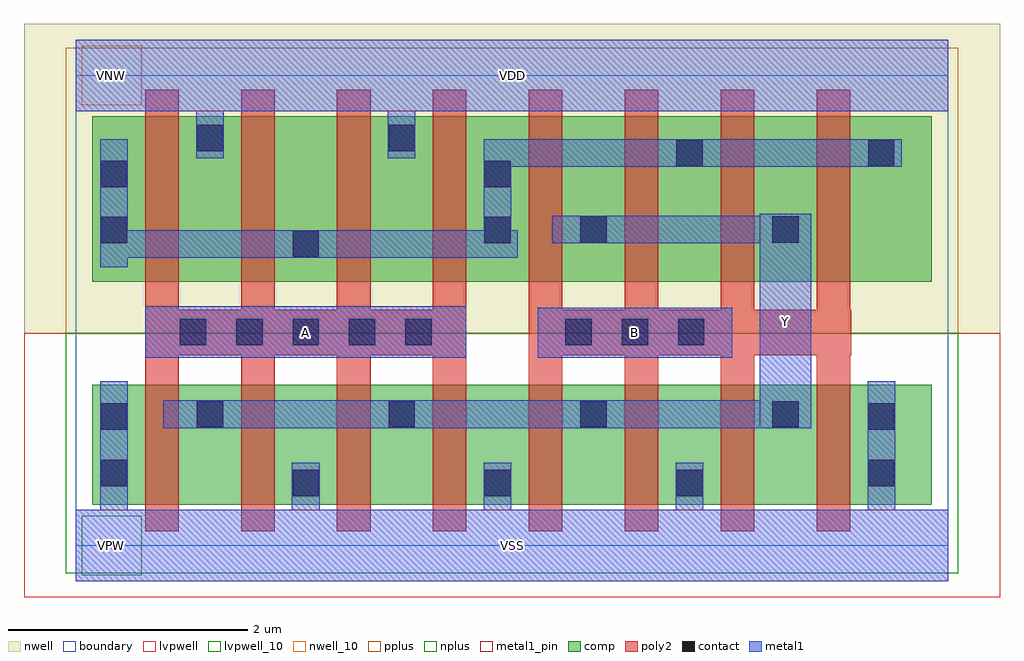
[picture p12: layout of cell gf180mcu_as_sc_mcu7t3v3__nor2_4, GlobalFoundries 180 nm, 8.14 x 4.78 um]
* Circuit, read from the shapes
.subckt gf180mcu_as_sc_mcu7t3v3__nor2_4 A B VDD VNW VSS Y
XM1 Y A VSS VSUBS nfet_03v3 w=1u l=0.28u m=4
XM2 Y B VSS VSUBS nfet_03v3 w=1u l=0.28u m=4
XM3 VDD A n1 VNW pfet_03v3 w=1.38u l=0.28u m=4
XM4 Y B n1 VNW pfet_03v3 w=1.38u l=0.28u m=4
.ends

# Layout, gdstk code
import gdstk
lib = gdstk.Library(unit=1e-6, precision=1e-09)
def R(c, l, rs):  # rectangles x0, y0, x1, y1
    for r in rs: c.add(gdstk.rectangle(r[:2], r[2:], *l))
def A(c, l, x, y, w, h, nx, ny, dx, dy):  # array of equal rectangles
    R(c, l, [(x+i*dx, y+j*dy, x+i*dx+w, y+j*dy+h) for i in range(nx) for j in range(ny)])
boundary = (0, 0)
nwell = (21, 0)
nwell_10 = (21, 10)
comp = (22, 0)
poly2 = (30, 0)
pplus = (31, 0)
nplus = (32, 0)
contact = (33, 0)
metal1 = (34, 0)
metal1_pin = (34, 10)
lvpwell = (204, 0)
lvpwell_10 = (204, 10)

gf180mcu_as_sc_mcu7t3v3_ = lib.new_cell('gf180mcu_as_sc_mcu7t3v3__nor2_4')
R(gf180mcu_as_sc_mcu7t3v3_, boundary, [(0,0,7.28,3.92)])
R(gf180mcu_as_sc_mcu7t3v3_, nwell, [(-0.43,1.77,7.71,4.35)])
R(gf180mcu_as_sc_mcu7t3v3_, nwell_10, [(0.05,3.67,0.55,4.17)])
R(gf180mcu_as_sc_mcu7t3v3_, comp, [(0.14,0.34,7.14,1.34), (0.14,2.2,7.14,3.58)])
A(gf180mcu_as_sc_mcu7t3v3_, poly2, 0.58, 0.12, 0.28, 1.465, 8, 1, 0.8, 0)
A(gf180mcu_as_sc_mcu7t3v3_, poly2, 0.58, 1.965, 0.28, 1.835, 8, 1, 0.8, 0)
R(gf180mcu_as_sc_mcu7t3v3_, poly2, [(0.58,1.585,3.26,1.965), (3.78,1.585,6.47,1.965)])
R(gf180mcu_as_sc_mcu7t3v3_, pplus, [(-0.08,1.77,7.36,4.15)])
R(gf180mcu_as_sc_mcu7t3v3_, nplus, [(-0.08,-0.23,7.36,1.77)])
A(gf180mcu_as_sc_mcu7t3v3_, contact, 1.81, 0.41, 0.22, 0.22, 3, 1, 1.6, 0)
A(gf180mcu_as_sc_mcu7t3v3_, contact, 1.01, 0.985, 0.22, 0.22, 4, 1, 1.6, 0)
A(gf180mcu_as_sc_mcu7t3v3_, contact, 0.87, 1.67, 0.22, 0.22, 5, 1, 0.47, 0)
A(gf180mcu_as_sc_mcu7t3v3_, contact, 4.085, 1.67, 0.22, 0.22, 3, 1, 0.47, 0)
R(gf180mcu_as_sc_mcu7t3v3_, contact, [(0.21,0.495,0.43,0.715), (6.61,0.495,6.83,0.715), (0.21,0.965,0.43,1.185), (6.61,0.965,6.83,1.185), (1.81,2.405,2.03,2.625), (0.21,2.52,0.43,2.74), (3.41,2.52,3.63,2.74), (4.21,2.525,4.43,2.745), (5.81,2.525,6.03,2.745), (0.21,2.99,0.43,3.21), (3.41,2.99,3.63,3.21), (5.01,3.165,5.23,3.385), (6.61,3.165,6.83,3.385), (1.01,3.29,1.23,3.51), (2.61,3.29,2.83,3.51)])
A(gf180mcu_as_sc_mcu7t3v3_, metal1, 1.805, 0.3, 0.23, 0.39, 3, 1, 1.6, 0)
R(gf180mcu_as_sc_mcu7t3v3_, metal1, [(0,-0.3,7.28,0.3), (0.205,0.3,0.435,1.37), (6.605,0.3,6.835,1.37), (0.73,0.98,6.135,1.21), (5.705,1.21,6.135,2.52), (0.58,1.565,3.26,1.995), (3.855,1.565,5.475,1.985), (0.205,2.32,0.435,2.4), (0.205,2.4,3.69,2.63), (3.975,2.52,6.135,2.75), (0.205,2.63,0.435,3.39), (3.405,2.63,3.635,3.16), (5.705,2.75,6.135,2.765), (3.405,3.16,6.89,3.39), (1.005,3.23,1.235,3.62), (2.605,3.23,2.835,3.62), (0,3.62,7.28,4.22)])
R(gf180mcu_as_sc_mcu7t3v3_, metal1_pin, [(0,-0.3,7.28,0.3), (5.705,0.98,6.135,2.765), (0.58,1.565,3.26,1.995), (3.855,1.565,5.475,1.985), (0,3.62,7.28,4.22)])
R(gf180mcu_as_sc_mcu7t3v3_, lvpwell, [(-0.43,-0.43,7.71,1.77)])
R(gf180mcu_as_sc_mcu7t3v3_, lvpwell_10, [(0.05,-0.25,0.55,0.25)])
gf180mcu_as_sc_mcu7t3v3_.add(gdstk.Label('VDD', (3.64,3.92), layer=34, texttype=10))
gf180mcu_as_sc_mcu7t3v3_.add(gdstk.Label('VSS', (3.64,0), layer=34, texttype=10))
gf180mcu_as_sc_mcu7t3v3_.add(gdstk.Label('Y', (5.92,1.872), layer=34, texttype=10))
gf180mcu_as_sc_mcu7t3v3_.add(gdstk.Label('A', (1.92,1.78), layer=34, texttype=10))
gf180mcu_as_sc_mcu7t3v3_.add(gdstk.Label('B', (4.665,1.775), layer=34, texttype=10))
gf180mcu_as_sc_mcu7t3v3_.add(gdstk.Label('VNW', (0.3,3.92), layer=21, texttype=10))
gf180mcu_as_sc_mcu7t3v3_.add(gdstk.Label('VPW', (0.3,0), layer=204, texttype=10))

lib.write_gds('gf180mcu_as_sc_mcu7t3v3__nor2_4.gds')
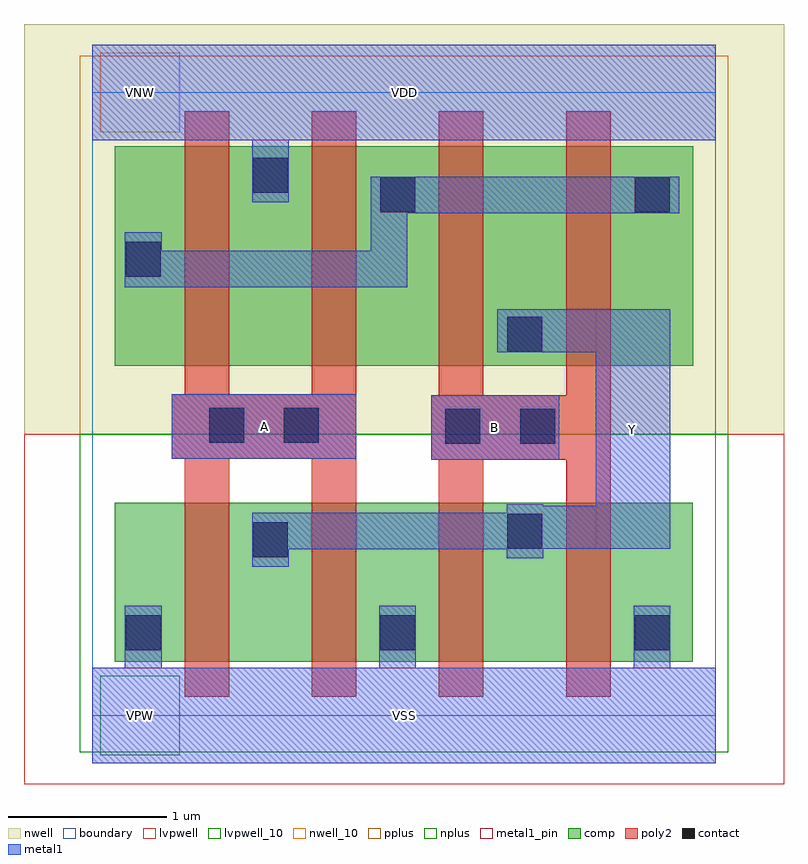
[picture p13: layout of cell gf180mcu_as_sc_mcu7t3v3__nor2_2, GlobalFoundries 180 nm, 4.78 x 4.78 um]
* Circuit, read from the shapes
.subckt gf180mcu_as_sc_mcu7t3v3__nor2_2 A B VDD VNW VSS Y
XM1 Y A VSS VSUBS nfet_03v3 w=1u l=0.28u m=2
XM2 Y B VSS VSUBS nfet_03v3 w=1u l=0.28u m=2
XM3 VDD A n1 VNW pfet_03v3 w=1.38u l=0.28u m=2
XM4 Y B n1 VNW pfet_03v3 w=1.38u l=0.28u m=2
.ends

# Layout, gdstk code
import gdstk
lib = gdstk.Library(unit=1e-6, precision=1e-09)
def R(c, l, rs):  # rectangles x0, y0, x1, y1
    for r in rs: c.add(gdstk.rectangle(r[:2], r[2:], *l))
def A(c, l, x, y, w, h, nx, ny, dx, dy):  # array of equal rectangles
    R(c, l, [(x+i*dx, y+j*dy, x+i*dx+w, y+j*dy+h) for i in range(nx) for j in range(ny)])
boundary = (0, 0)
nwell = (21, 0)
nwell_10 = (21, 10)
comp = (22, 0)
poly2 = (30, 0)
pplus = (31, 0)
nplus = (32, 0)
contact = (33, 0)
metal1 = (34, 0)
metal1_pin = (34, 10)
lvpwell = (204, 0)
lvpwell_10 = (204, 10)

gf180mcu_as_sc_mcu7t3v3_ = lib.new_cell('gf180mcu_as_sc_mcu7t3v3__nor2_2')
R(gf180mcu_as_sc_mcu7t3v3_, boundary, [(0,0,3.92,3.92)])
R(gf180mcu_as_sc_mcu7t3v3_, nwell, [(-0.43,1.77,4.35,4.35)])
R(gf180mcu_as_sc_mcu7t3v3_, nwell_10, [(0.05,3.67,0.55,4.17)])
R(gf180mcu_as_sc_mcu7t3v3_, comp, [(0.14,0.34,3.775,1.34), (0.14,2.2,3.78,3.58)])
R(gf180mcu_as_sc_mcu7t3v3_, poly2, [(0.58,0.12,0.86,1.615), (1.38,0.12,1.66,1.615), (2.18,0.12,2.46,1.61), (2.98,0.12,3.26,1.61), (2.13,1.61,3.26,2.015), (0.5,1.615,1.66,2.02), (2.18,2.015,2.46,3.8), (2.98,2.015,3.26,3.8), (0.58,2.02,0.86,3.8), (1.38,2.02,1.66,3.8)])
R(gf180mcu_as_sc_mcu7t3v3_, pplus, [(-0.08,1.77,4,4.15)])
R(gf180mcu_as_sc_mcu7t3v3_, nplus, [(-0.08,-0.23,4,1.77)])
A(gf180mcu_as_sc_mcu7t3v3_, contact, 0.21, 0.41, 0.22, 0.22, 3, 1, 1.6, 0)
R(gf180mcu_as_sc_mcu7t3v3_, contact, [(1.01,0.995,1.23,1.215), (2.61,1.05,2.83,1.27), (2.22,1.71,2.44,1.93), (2.69,1.71,2.91,1.93), (0.735,1.715,0.955,1.935), (1.205,1.715,1.425,1.935), (2.61,2.29,2.83,2.51), (0.21,2.76,0.43,2.98), (1.81,3.165,2.03,3.385), (3.41,3.165,3.63,3.385), (1.01,3.29,1.23,3.51)])
A(gf180mcu_as_sc_mcu7t3v3_, metal1, 0.205, 0.3, 0.23, 0.39, 3, 1, 1.6, 0)
R(gf180mcu_as_sc_mcu7t3v3_, metal1, [(0,-0.3,3.92,0.3), (1.005,0.935,1.235,1.045), (2.605,0.99,2.835,1.045), (1.005,1.045,2.835,1.05), (1.005,1.05,3.635,1.275), (2.605,1.275,3.635,1.32), (2.605,1.32,2.835,1.33), (3.165,1.32,3.635,2.285), (2.13,1.61,2.935,2.015), (0.5,1.615,1.66,2.02), (2.545,2.285,3.635,2.555), (0.205,2.695,1.98,2.925), (0.205,2.925,0.435,3.04), (1.75,2.925,1.98,3.16), (1.75,3.16,3.69,3.39), (1.005,3.23,1.235,3.62), (0,3.62,3.92,4.22)])
R(gf180mcu_as_sc_mcu7t3v3_, metal1_pin, [(0,-0.3,3.92,0.3), (3.165,1.05,3.635,2.555), (2.13,1.61,2.935,2.015), (0.5,1.615,1.66,2.02), (0,3.62,3.92,4.22)])
R(gf180mcu_as_sc_mcu7t3v3_, lvpwell, [(-0.43,-0.43,4.35,1.77)])
R(gf180mcu_as_sc_mcu7t3v3_, lvpwell_10, [(0.05,-0.25,0.55,0.25)])
gf180mcu_as_sc_mcu7t3v3_.add(gdstk.Label('VDD', (1.96,3.92), layer=34, texttype=10))
gf180mcu_as_sc_mcu7t3v3_.add(gdstk.Label('VSS', (1.96,0), layer=34, texttype=10))
gf180mcu_as_sc_mcu7t3v3_.add(gdstk.Label('Y', (3.4,1.802), layer=34, texttype=10))
gf180mcu_as_sc_mcu7t3v3_.add(gdstk.Label('B', (2.532,1.812), layer=34, texttype=10))
gf180mcu_as_sc_mcu7t3v3_.add(gdstk.Label('A', (1.08,1.817), layer=34, texttype=10))
gf180mcu_as_sc_mcu7t3v3_.add(gdstk.Label('VNW', (0.3,3.92), layer=21, texttype=10))
gf180mcu_as_sc_mcu7t3v3_.add(gdstk.Label('VPW', (0.3,0), layer=204, texttype=10))

lib.write_gds('gf180mcu_as_sc_mcu7t3v3__nor2_2.gds')
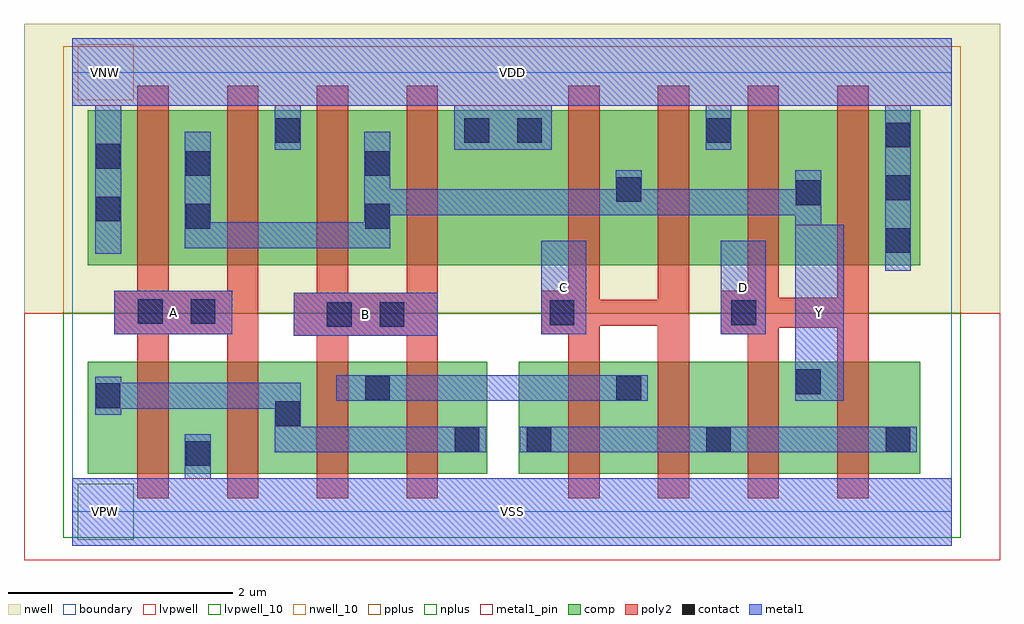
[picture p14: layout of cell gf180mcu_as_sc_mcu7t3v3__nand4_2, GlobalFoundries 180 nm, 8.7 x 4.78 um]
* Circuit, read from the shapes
.subckt gf180mcu_as_sc_mcu7t3v3__nand4_2 A B C D VDD VNW VSS Y
XM1 VSS A n1 VSUBS nfet_03v3 w=1u l=0.28u m=2
XM2 n2 B n1 VSUBS nfet_03v3 w=1u l=0.28u m=2
XM3 n2 C n3 VSUBS nfet_03v3 w=1u l=0.28u m=2
XM4 Y D n3 VSUBS nfet_03v3 w=1u l=0.28u m=2
XM5 Y A VDD VNW pfet_03v3 w=1.38u l=0.28u m=2
XM6 Y B VDD VNW pfet_03v3 w=1.38u l=0.28u m=2
XM7 Y C VDD VNW pfet_03v3 w=1.38u l=0.28u m=2
XM8 Y D VDD VNW pfet_03v3 w=1.38u l=0.28u m=2
.ends

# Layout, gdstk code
import gdstk
lib = gdstk.Library(unit=1e-6, precision=1e-09)
def R(c, l, rs):  # rectangles x0, y0, x1, y1
    for r in rs: c.add(gdstk.rectangle(r[:2], r[2:], *l))
def A(c, l, x, y, w, h, nx, ny, dx, dy):  # array of equal rectangles
    R(c, l, [(x+i*dx, y+j*dy, x+i*dx+w, y+j*dy+h) for i in range(nx) for j in range(ny)])
boundary = (0, 0)
nwell = (21, 0)
nwell_10 = (21, 10)
comp = (22, 0)
poly2 = (30, 0)
pplus = (31, 0)
nplus = (32, 0)
contact = (33, 0)
metal1 = (34, 0)
metal1_pin = (34, 10)
lvpwell = (204, 0)
lvpwell_10 = (204, 10)

gf180mcu_as_sc_mcu7t3v3_ = lib.new_cell('gf180mcu_as_sc_mcu7t3v3__nand4_2')
R(gf180mcu_as_sc_mcu7t3v3_, boundary, [(0,0,7.84,3.92)])
R(gf180mcu_as_sc_mcu7t3v3_, nwell, [(-0.43,1.77,8.27,4.35)])
R(gf180mcu_as_sc_mcu7t3v3_, nwell_10, [(0.05,3.67,0.55,4.17)])
R(gf180mcu_as_sc_mcu7t3v3_, comp, [(0.14,0.34,3.7,1.34), (3.98,0.34,7.56,1.34), (0.14,2.2,7.56,3.58)])
R(gf180mcu_as_sc_mcu7t3v3_, poly2, [(0.58,0.12,0.86,1.585), (1.38,0.12,1.66,1.585), (2.18,0.12,2.46,1.57), (2.98,0.12,3.26,1.57), (4.42,0.12,4.7,1.585), (5.22,0.12,5.5,1.66), (6.02,0.12,6.3,1.585), (6.82,0.12,7.1,1.64), (1.975,1.57,3.26,1.955), (0.375,1.585,1.66,1.97), (4.18,1.585,4.7,1.66), (5.78,1.585,6.3,1.64), (5.78,1.64,7.1,1.91), (4.18,1.66,5.5,1.89), (4.18,1.89,4.7,1.97), (5.22,1.89,5.5,3.8), (5.78,1.91,6.3,1.97), (6.82,1.91,7.1,3.8), (2.18,1.955,2.46,3.8), (2.98,1.955,3.26,3.8), (0.58,1.97,0.86,3.8), (1.38,1.97,1.66,3.8), (4.42,1.97,4.7,3.8), (6.02,1.97,6.3,3.8)])
R(gf180mcu_as_sc_mcu7t3v3_, pplus, [(-0.08,1.77,7.92,4.15)])
R(gf180mcu_as_sc_mcu7t3v3_, nplus, [(-0.08,-0.23,7.92,1.77)])
A(gf180mcu_as_sc_mcu7t3v3_, contact, 4.05, 0.535, 0.22, 0.22, 3, 1, 1.6, 0)
A(gf180mcu_as_sc_mcu7t3v3_, contact, 7.25, 2.31, 0.22, 0.22, 1, 3, 0, 0.47)
R(gf180mcu_as_sc_mcu7t3v3_, contact, [(1.01,0.41,1.23,0.63), (3.41,0.535,3.63,0.755), (1.81,0.765,2.03,0.985), (0.21,0.925,0.43,1.145), (2.61,0.995,2.83,1.215), (4.85,0.995,5.07,1.215), (6.45,1.05,6.67,1.27), (2.27,1.65,2.49,1.87), (2.74,1.65,2.96,1.87), (4.255,1.665,4.475,1.885), (5.875,1.665,6.095,1.885), (0.585,1.675,0.805,1.895), (1.055,1.675,1.275,1.895), (1.01,2.525,1.23,2.745), (2.61,2.525,2.83,2.745), (0.21,2.59,0.43,2.81), (6.45,2.735,6.67,2.955), (4.85,2.765,5.07,2.985), (1.01,2.995,1.23,3.215), (2.61,2.995,2.83,3.215), (0.21,3.06,0.43,3.28), (1.81,3.29,2.03,3.51), (3.495,3.29,3.715,3.51), (3.965,3.29,4.185,3.51), (5.65,3.29,5.87,3.51)])
R(gf180mcu_as_sc_mcu7t3v3_, metal1, [(0,-0.3,7.84,0.3), (1.005,0.3,1.235,0.69), (1.805,0.53,3.69,0.76), (3.99,0.53,7.53,0.76), (1.805,0.76,2.035,0.92), (0.205,0.865,0.435,0.92), (0.205,0.92,2.035,1.15), (2.355,0.99,5.13,1.22), (6.445,0.99,6.875,2.56), (0.205,1.15,0.435,1.205), (1.975,1.57,3.26,1.955), (0.375,1.585,1.425,1.97), (4.18,1.585,4.58,2.415), (5.78,1.585,6.18,2.415), (7.245,2.15,7.475,3.62), (0.205,2.3,0.435,3.62), (1.005,2.35,2.835,2.58), (6.445,2.56,6.675,2.645), (1.005,2.58,1.235,3.39), (2.605,2.58,2.835,2.645), (2.605,2.645,6.675,2.875), (2.605,2.875,2.835,3.39), (4.845,2.875,5.075,3.045), (6.445,2.875,6.675,3.045), (1.805,3.23,2.035,3.62), (3.405,3.23,4.275,3.62), (5.645,3.23,5.875,3.62), (0,3.62,7.84,4.22)])
R(gf180mcu_as_sc_mcu7t3v3_, metal1_pin, [(0,-0.3,7.84,0.3), (6.445,0.99,6.875,2.56), (1.975,1.57,3.26,1.955), (0.375,1.585,1.425,1.97), (4.18,1.585,4.58,2.415), (5.78,1.585,6.18,2.415), (0,3.62,7.84,4.22)])
R(gf180mcu_as_sc_mcu7t3v3_, lvpwell, [(-0.43,-0.43,8.27,1.77)])
R(gf180mcu_as_sc_mcu7t3v3_, lvpwell_10, [(0.05,-0.25,0.55,0.25)])
gf180mcu_as_sc_mcu7t3v3_.add(gdstk.Label('VDD', (3.92,3.92), layer=34, texttype=10))
gf180mcu_as_sc_mcu7t3v3_.add(gdstk.Label('VSS', (3.92,0), layer=34, texttype=10))
gf180mcu_as_sc_mcu7t3v3_.add(gdstk.Label('A', (0.9,1.777), layer=34, texttype=10))
gf180mcu_as_sc_mcu7t3v3_.add(gdstk.Label('B', (2.617,1.762), layer=34, texttype=10))
gf180mcu_as_sc_mcu7t3v3_.add(gdstk.Label('C', (4.38,2), layer=34, texttype=10))
gf180mcu_as_sc_mcu7t3v3_.add(gdstk.Label('D', (5.98,2), layer=34, texttype=10))
gf180mcu_as_sc_mcu7t3v3_.add(gdstk.Label('Y', (6.66,1.775), layer=34, texttype=10))
gf180mcu_as_sc_mcu7t3v3_.add(gdstk.Label('VNW', (0.3,3.92), layer=21, texttype=10))
gf180mcu_as_sc_mcu7t3v3_.add(gdstk.Label('VPW', (0.3,0), layer=204, texttype=10))

lib.write_gds('gf180mcu_as_sc_mcu7t3v3__nand4_2.gds')
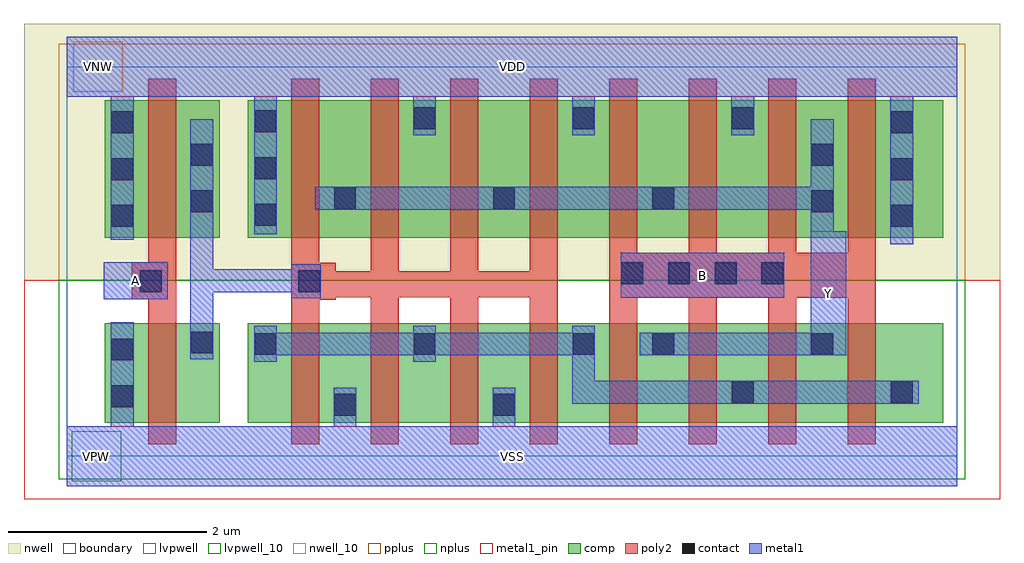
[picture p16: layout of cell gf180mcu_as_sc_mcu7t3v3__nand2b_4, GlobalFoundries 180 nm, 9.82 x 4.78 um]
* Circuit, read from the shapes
.subckt gf180mcu_as_sc_mcu7t3v3__nand2b_4 A B VDD VNW VSS Y
XM1 n1 A VSS VSUBS nfet_03v3 w=1u l=0.28u
XM2 VSS n1 n2 VSUBS nfet_03v3 w=1u l=0.28u m=4
XM3 Y B n2 VSUBS nfet_03v3 w=1u l=0.28u m=4
XM4 n1 A VDD VNW pfet_03v3 w=1.38u l=0.28u
XM5 Y n1 VDD VNW pfet_03v3 w=1.38u l=0.28u m=4
XM6 Y B VDD VNW pfet_03v3 w=1.38u l=0.28u m=4
.ends

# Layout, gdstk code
import gdstk
lib = gdstk.Library(unit=1e-6, precision=1e-09)
def R(c, l, rs):  # rectangles x0, y0, x1, y1
    for r in rs: c.add(gdstk.rectangle(r[:2], r[2:], *l))
def A(c, l, x, y, w, h, nx, ny, dx, dy):  # array of equal rectangles
    R(c, l, [(x+i*dx, y+j*dy, x+i*dx+w, y+j*dy+h) for i in range(nx) for j in range(ny)])
boundary = (0, 0)
nwell = (21, 0)
nwell_10 = (21, 10)
comp = (22, 0)
poly2 = (30, 0)
pplus = (31, 0)
nplus = (32, 0)
contact = (33, 0)
metal1 = (34, 0)
metal1_pin = (34, 10)
lvpwell = (204, 0)
lvpwell_10 = (204, 10)

gf180mcu_as_sc_mcu7t3v3_ = lib.new_cell('gf180mcu_as_sc_mcu7t3v3__nand2b_4')
R(gf180mcu_as_sc_mcu7t3v3_, boundary, [(0,0,8.96,3.92)])
R(gf180mcu_as_sc_mcu7t3v3_, nwell, [(-0.43,1.77,9.39,4.35)])
R(gf180mcu_as_sc_mcu7t3v3_, nwell_10, [(0.065,3.67,0.565,4.17)])
R(gf180mcu_as_sc_mcu7t3v3_, comp, [(0.38,0.34,1.54,1.34), (1.82,0.34,8.82,1.34), (0.38,2.2,1.54,3.58), (1.82,2.2,8.82,3.58)])
A(gf180mcu_as_sc_mcu7t3v3_, poly2, 3.06, 0.12, 0.28, 1.48, 3, 1, 0.8, 0)
A(gf180mcu_as_sc_mcu7t3v3_, poly2, 5.46, 0.12, 0.28, 1.475, 4, 1, 0.8, 0)
A(gf180mcu_as_sc_mcu7t3v3_, poly2, 3.06, 1.86, 0.28, 1.94, 3, 1, 0.8, 0)
A(gf180mcu_as_sc_mcu7t3v3_, poly2, 5.46, 2.05, 0.28, 1.75, 4, 1, 0.8, 0)
R(gf180mcu_as_sc_mcu7t3v3_, poly2, [(0.82,0.12,1.1,1.58), (2.26,0.12,2.54,1.575), (2.26,1.575,2.705,1.6), (0.655,1.58,1.1,1.95), (5.46,1.595,8.14,2.05), (2.26,1.6,4.94,1.86), (2.26,1.86,2.705,1.945), (2.26,1.945,2.54,3.8), (0.82,1.95,1.1,3.8)])
R(gf180mcu_as_sc_mcu7t3v3_, pplus, [(-0.08,1.77,9.04,4.15)])
R(gf180mcu_as_sc_mcu7t3v3_, nplus, [(-0.08,-0.23,9.04,1.77)])
A(gf180mcu_as_sc_mcu7t3v3_, contact, 1.89, 1.02, 0.22, 0.22, 3, 1, 1.6, 0)
A(gf180mcu_as_sc_mcu7t3v3_, contact, 5.58, 1.73, 0.22, 0.22, 4, 1, 0.47, 0)
A(gf180mcu_as_sc_mcu7t3v3_, contact, 0.45, 2.31, 0.22, 0.22, 1, 3, 0, 0.47)
A(gf180mcu_as_sc_mcu7t3v3_, contact, 8.29, 2.31, 0.22, 0.22, 1, 3, 0, 0.47)
A(gf180mcu_as_sc_mcu7t3v3_, contact, 1.89, 2.32, 0.22, 0.22, 1, 3, 0, 0.47)
A(gf180mcu_as_sc_mcu7t3v3_, contact, 2.69, 2.485, 0.22, 0.22, 3, 1, 1.6, 0)
A(gf180mcu_as_sc_mcu7t3v3_, contact, 3.49, 3.29, 0.22, 0.22, 3, 1, 1.6, 0)
R(gf180mcu_as_sc_mcu7t3v3_, contact, [(2.69,0.41,2.91,0.63), (4.29,0.41,4.51,0.63), (0.45,0.495,0.67,0.715), (6.69,0.535,6.91,0.755), (8.29,0.535,8.51,0.755), (0.45,0.965,0.67,1.185), (5.89,1.02,6.11,1.24), (7.49,1.02,7.71,1.24), (1.25,1.035,1.47,1.255), (0.735,1.65,0.955,1.87), (2.33,1.65,2.55,1.87), (1.25,2.455,1.47,2.675), (7.49,2.455,7.71,2.675), (1.25,2.925,1.47,3.145), (7.49,2.925,7.71,3.145)])
A(gf180mcu_as_sc_mcu7t3v3_, metal1, 1.885, 1.245, 0.23, 0.07, 3, 1, 1.6, 0)
A(gf180mcu_as_sc_mcu7t3v3_, metal1, 3.485, 3.23, 0.23, 0.39, 3, 1, 1.6, 0)
R(gf180mcu_as_sc_mcu7t3v3_, metal1, [(0,-0.3,8.96,0.3), (0.445,0.3,0.675,1.35), (2.685,0.3,2.915,0.69), (4.285,0.3,4.515,0.69), (5.085,0.53,8.57,0.76), (5.085,0.76,5.315,1.015), (1.885,0.95,2.115,1.015), (3.485,0.95,3.715,1.015), (1.245,0.975,1.475,1.65), (1.885,1.015,5.315,1.245), (5.765,1.015,7.845,1.245), (7.485,1.245,7.845,2.265), (0.37,1.58,1.015,1.95), (2.26,1.59,2.555,1.65), (5.575,1.595,7.22,2.05), (1.245,1.65,2.555,1.88), (1.245,1.88,1.475,3.39), (2.26,1.88,2.555,1.93), (8.285,2.135,8.515,3.62), (0.445,2.18,0.675,3.62), (1.885,2.235,2.115,3.62), (7.485,2.265,7.715,2.48), (2.5,2.48,7.715,2.71), (7.485,2.71,7.715,3.39), (0,3.62,8.96,4.22)])
R(gf180mcu_as_sc_mcu7t3v3_, metal1_pin, [(0,-0.3,8.96,0.3), (7.485,1.015,7.845,2.265), (0.37,1.58,1.015,1.95), (5.575,1.595,7.22,2.05), (0,3.62,8.96,4.22)])
R(gf180mcu_as_sc_mcu7t3v3_, lvpwell, [(-0.43,-0.43,9.39,1.77)])
R(gf180mcu_as_sc_mcu7t3v3_, lvpwell_10, [(0.05,-0.25,0.55,0.25)])
gf180mcu_as_sc_mcu7t3v3_.add(gdstk.Label('VDD', (4.48,3.92), layer=34, texttype=10))
gf180mcu_as_sc_mcu7t3v3_.add(gdstk.Label('VSS', (4.48,0), layer=34, texttype=10))
gf180mcu_as_sc_mcu7t3v3_.add(gdstk.Label('Y', (7.665,1.64), layer=34, texttype=10))
gf180mcu_as_sc_mcu7t3v3_.add(gdstk.Label('A', (0.692,1.765), layer=34, texttype=10))
gf180mcu_as_sc_mcu7t3v3_.add(gdstk.Label('B', (6.397,1.822), layer=34, texttype=10))
gf180mcu_as_sc_mcu7t3v3_.add(gdstk.Label('VNW', (0.315,3.92), layer=21, texttype=10))
gf180mcu_as_sc_mcu7t3v3_.add(gdstk.Label('VPW', (0.3,0), layer=204, texttype=10))

lib.write_gds('gf180mcu_as_sc_mcu7t3v3__nand2b_4.gds')
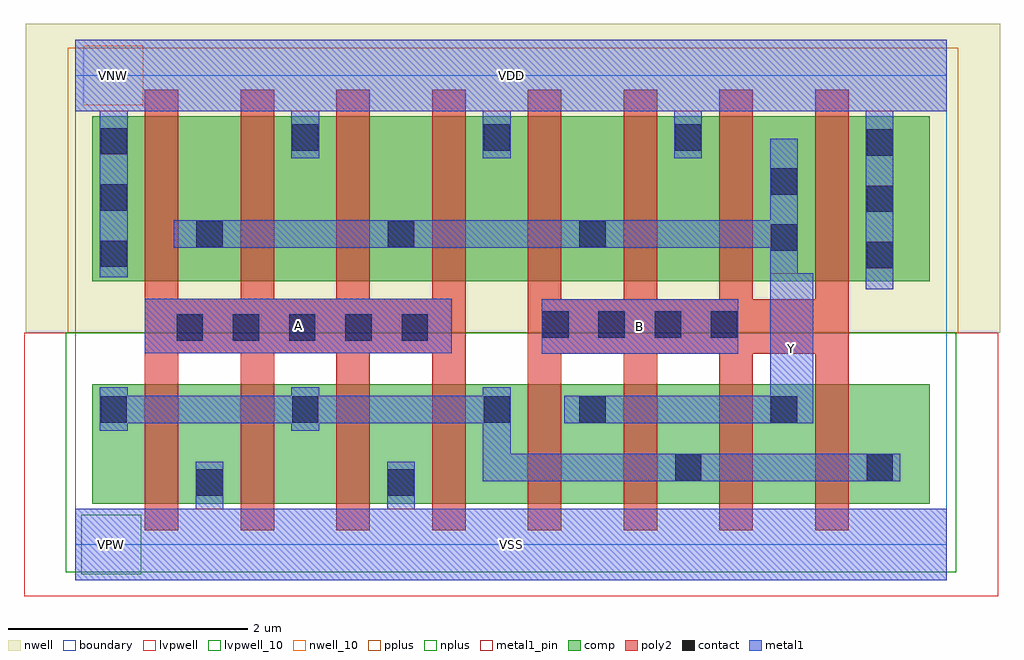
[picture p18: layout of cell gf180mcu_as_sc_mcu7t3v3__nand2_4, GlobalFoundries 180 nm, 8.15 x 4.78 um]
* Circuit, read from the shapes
.subckt gf180mcu_as_sc_mcu7t3v3__nand2_4 A B VDD VNW VSS Y
XM1 VSS A n1 VSUBS nfet_03v3 w=1u l=0.28u m=4
XM2 Y B n1 VSUBS nfet_03v3 w=1u l=0.28u m=4
XM3 Y A VDD VNW pfet_03v3 w=1.38u l=0.28u m=4
XM4 Y B VDD VNW pfet_03v3 w=1.38u l=0.28u m=4
.ends

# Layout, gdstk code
import gdstk
lib = gdstk.Library(unit=1e-6, precision=1e-09)
def R(c, l, rs):  # rectangles x0, y0, x1, y1
    for r in rs: c.add(gdstk.rectangle(r[:2], r[2:], *l))
def A(c, l, x, y, w, h, nx, ny, dx, dy):  # array of equal rectangles
    R(c, l, [(x+i*dx, y+j*dy, x+i*dx+w, y+j*dy+h) for i in range(nx) for j in range(ny)])
boundary = (0, 0)
nwell = (21, 0)
nwell_10 = (21, 10)
comp = (22, 0)
poly2 = (30, 0)
pplus = (31, 0)
nplus = (32, 0)
contact = (33, 0)
metal1 = (34, 0)
metal1_pin = (34, 10)
lvpwell = (204, 0)
lvpwell_10 = (204, 10)

gf180mcu_as_sc_mcu7t3v3_ = lib.new_cell('gf180mcu_as_sc_mcu7t3v3__nand2_4')
R(gf180mcu_as_sc_mcu7t3v3_, boundary, [(0,0,7.28,3.92)])
R(gf180mcu_as_sc_mcu7t3v3_, nwell, [(-0.415,1.77,7.725,4.35)])
R(gf180mcu_as_sc_mcu7t3v3_, nwell_10, [(0.065,3.67,0.565,4.17)])
R(gf180mcu_as_sc_mcu7t3v3_, comp, [(0.14,0.34,7.14,1.34), (0.14,2.2,7.14,3.58)])
A(gf180mcu_as_sc_mcu7t3v3_, poly2, 0.58, 0.12, 0.28, 1.48, 4, 1, 0.8, 0)
A(gf180mcu_as_sc_mcu7t3v3_, poly2, 3.78, 0.12, 0.28, 1.475, 4, 1, 0.8, 0)
A(gf180mcu_as_sc_mcu7t3v3_, poly2, 3.78, 2.05, 0.28, 1.75, 4, 1, 0.8, 0)
A(gf180mcu_as_sc_mcu7t3v3_, poly2, 0.58, 2.055, 0.28, 1.745, 4, 1, 0.8, 0)
R(gf180mcu_as_sc_mcu7t3v3_, poly2, [(3.78,1.595,6.46,2.05), (0.58,1.6,3.26,2.055)])
R(gf180mcu_as_sc_mcu7t3v3_, pplus, [(-0.065,1.77,7.375,4.15)])
R(gf180mcu_as_sc_mcu7t3v3_, nplus, [(-0.08,-0.23,7.36,1.77)])
A(gf180mcu_as_sc_mcu7t3v3_, contact, 0.21, 1.02, 0.22, 0.22, 3, 1, 1.6, 0)
A(gf180mcu_as_sc_mcu7t3v3_, contact, 0.845, 1.705, 0.22, 0.22, 5, 1, 0.47, 0)
A(gf180mcu_as_sc_mcu7t3v3_, contact, 3.9, 1.73, 0.22, 0.22, 4, 1, 0.47, 0)
A(gf180mcu_as_sc_mcu7t3v3_, contact, 6.61, 2.31, 0.22, 0.22, 1, 3, 0, 0.47)
A(gf180mcu_as_sc_mcu7t3v3_, contact, 0.21, 2.32, 0.22, 0.22, 1, 3, 0, 0.47)
A(gf180mcu_as_sc_mcu7t3v3_, contact, 1.01, 2.485, 0.22, 0.22, 3, 1, 1.6, 0)
A(gf180mcu_as_sc_mcu7t3v3_, contact, 1.81, 3.29, 0.22, 0.22, 3, 1, 1.6, 0)
R(gf180mcu_as_sc_mcu7t3v3_, contact, [(1.01,0.41,1.23,0.63), (2.61,0.41,2.83,0.63), (5.01,0.535,5.23,0.755), (6.61,0.535,6.83,0.755), (4.21,1.02,4.43,1.24), (5.81,1.02,6.03,1.24), (5.81,2.455,6.03,2.675), (5.81,2.925,6.03,3.145)])
A(gf180mcu_as_sc_mcu7t3v3_, metal1, 0.205, 1.245, 0.23, 0.07, 3, 1, 1.6, 0)
A(gf180mcu_as_sc_mcu7t3v3_, metal1, 1.805, 3.23, 0.23, 0.39, 3, 1, 1.6, 0)
R(gf180mcu_as_sc_mcu7t3v3_, metal1, [(0,-0.3,7.28,0.3), (1.005,0.3,1.235,0.69), (2.605,0.3,2.835,0.69), (3.405,0.53,6.89,0.76), (3.405,0.76,3.635,1.015), (0.205,0.95,0.435,1.015), (1.805,0.95,2.035,1.015), (0.205,1.015,3.635,1.245), (4.085,1.015,6.165,1.245), (5.805,1.245,6.165,2.265), (3.895,1.595,5.54,2.05), (0.58,1.6,3.145,2.055), (6.605,2.135,6.835,3.62), (0.205,2.235,0.435,3.62), (5.805,2.265,6.035,2.48), (0.82,2.48,6.035,2.71), (5.805,2.71,6.035,3.39), (0,3.62,7.28,4.22)])
R(gf180mcu_as_sc_mcu7t3v3_, metal1_pin, [(0,-0.3,7.28,0.3), (5.805,1.015,6.165,2.265), (3.895,1.595,5.54,2.05), (0.58,1.6,3.145,2.055), (0,3.62,7.28,4.22)])
R(gf180mcu_as_sc_mcu7t3v3_, lvpwell, [(-0.43,-0.43,7.71,1.77)])
R(gf180mcu_as_sc_mcu7t3v3_, lvpwell_10, [(0.05,-0.25,0.55,0.25)])
gf180mcu_as_sc_mcu7t3v3_.add(gdstk.Label('VDD', (3.64,3.92), layer=34, texttype=10))
gf180mcu_as_sc_mcu7t3v3_.add(gdstk.Label('VSS', (3.64,0), layer=34, texttype=10))
gf180mcu_as_sc_mcu7t3v3_.add(gdstk.Label('Y', (5.985,1.64), layer=34, texttype=10))
gf180mcu_as_sc_mcu7t3v3_.add(gdstk.Label('A', (1.862,1.827), layer=34, texttype=10))
gf180mcu_as_sc_mcu7t3v3_.add(gdstk.Label('B', (4.717,1.822), layer=34, texttype=10))
gf180mcu_as_sc_mcu7t3v3_.add(gdstk.Label('VNW', (0.315,3.92), layer=21, texttype=10))
gf180mcu_as_sc_mcu7t3v3_.add(gdstk.Label('VPW', (0.3,0), layer=204, texttype=10))

lib.write_gds('gf180mcu_as_sc_mcu7t3v3__nand2_4.gds')
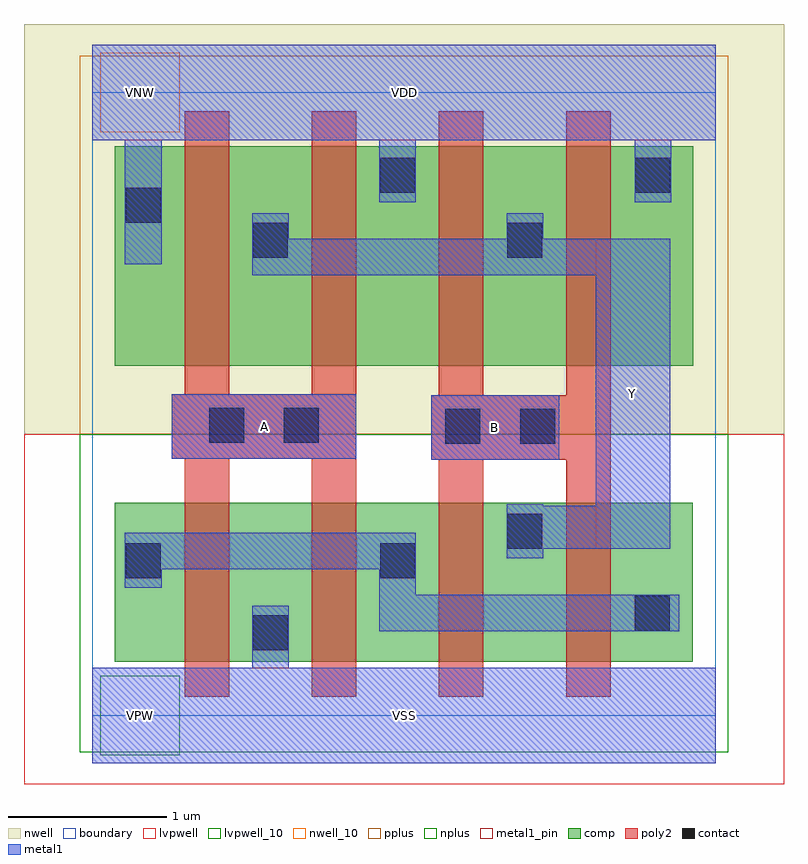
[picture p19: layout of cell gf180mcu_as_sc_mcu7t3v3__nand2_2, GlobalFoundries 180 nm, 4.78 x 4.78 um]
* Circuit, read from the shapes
.subckt gf180mcu_as_sc_mcu7t3v3__nand2_2 A B VDD VNW VSS Y
XM1 VSS A n1 VSUBS nfet_03v3 w=1u l=0.28u m=2
XM2 Y B n1 VSUBS nfet_03v3 w=1u l=0.28u m=2
XM3 Y A VDD VNW pfet_03v3 w=1.38u l=0.28u m=2
XM4 Y B VDD VNW pfet_03v3 w=1.38u l=0.28u m=2
.ends

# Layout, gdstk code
import gdstk
lib = gdstk.Library(unit=1e-6, precision=1e-09)
def R(c, l, rs):  # rectangles x0, y0, x1, y1
    for r in rs: c.add(gdstk.rectangle(r[:2], r[2:], *l))
boundary = (0, 0)
nwell = (21, 0)
nwell_10 = (21, 10)
comp = (22, 0)
poly2 = (30, 0)
pplus = (31, 0)
nplus = (32, 0)
contact = (33, 0)
metal1 = (34, 0)
metal1_pin = (34, 10)
lvpwell = (204, 0)
lvpwell_10 = (204, 10)

gf180mcu_as_sc_mcu7t3v3_ = lib.new_cell('gf180mcu_as_sc_mcu7t3v3__nand2_2')
R(gf180mcu_as_sc_mcu7t3v3_, boundary, [(0,0,3.92,3.92)])
R(gf180mcu_as_sc_mcu7t3v3_, nwell, [(-0.43,1.77,4.35,4.35)])
R(gf180mcu_as_sc_mcu7t3v3_, nwell_10, [(0.05,3.67,0.55,4.17)])
R(gf180mcu_as_sc_mcu7t3v3_, comp, [(0.14,0.34,3.775,1.34), (0.14,2.2,3.78,3.58)])
R(gf180mcu_as_sc_mcu7t3v3_, poly2, [(0.58,0.12,0.86,1.615), (1.38,0.12,1.66,1.615), (2.18,0.12,2.46,1.61), (2.98,0.12,3.26,1.61), (2.13,1.61,3.26,2.015), (0.5,1.615,1.66,2.02), (2.18,2.015,2.46,3.8), (2.98,2.015,3.26,3.8), (0.58,2.02,0.86,3.8), (1.38,2.02,1.66,3.8)])
R(gf180mcu_as_sc_mcu7t3v3_, pplus, [(-0.08,1.77,4,4.15)])
R(gf180mcu_as_sc_mcu7t3v3_, nplus, [(-0.08,-0.23,4,1.77)])
R(gf180mcu_as_sc_mcu7t3v3_, contact, [(1.01,0.41,1.23,0.63), (3.41,0.535,3.63,0.755), (0.21,0.865,0.43,1.085), (1.81,0.865,2.03,1.085), (2.61,1.05,2.83,1.27), (2.22,1.71,2.44,1.93), (2.69,1.71,2.91,1.93), (0.735,1.715,0.955,1.935), (1.205,1.715,1.425,1.935), (1.01,2.88,1.23,3.1), (2.61,2.88,2.83,3.1), (0.21,3.1,0.43,3.32), (1.81,3.29,2.03,3.51), (3.415,3.29,3.635,3.51)])
R(gf180mcu_as_sc_mcu7t3v3_, metal1, [(0,-0.3,3.92,0.3), (1.005,0.3,1.235,0.69), (1.805,0.53,3.69,0.76), (1.805,0.76,2.035,0.92), (0.205,0.805,0.435,0.92), (0.205,0.92,2.035,1.15), (2.605,0.99,2.835,1.05), (2.605,1.05,3.635,1.32), (2.605,1.32,2.835,1.33), (3.165,1.32,3.635,2.77), (2.13,1.61,2.935,2.015), (0.5,1.615,1.66,2.02), (1.005,2.77,3.635,3), (0.205,2.84,0.435,3.62), (1.005,3,1.235,3.16), (2.605,3,2.835,3.16), (1.805,3.23,2.035,3.62), (3.41,3.23,3.64,3.62), (0,3.62,3.92,4.22)])
R(gf180mcu_as_sc_mcu7t3v3_, metal1_pin, [(0,-0.3,3.92,0.3), (3.165,1.05,3.635,3), (2.13,1.61,2.935,2.015), (0.5,1.615,1.66,2.02), (0,3.62,3.92,4.22)])
R(gf180mcu_as_sc_mcu7t3v3_, lvpwell, [(-0.43,-0.43,4.35,1.77)])
R(gf180mcu_as_sc_mcu7t3v3_, lvpwell_10, [(0.05,-0.25,0.55,0.25)])
gf180mcu_as_sc_mcu7t3v3_.add(gdstk.Label('VDD', (1.96,3.92), layer=34, texttype=10))
gf180mcu_as_sc_mcu7t3v3_.add(gdstk.Label('VSS', (1.96,0), layer=34, texttype=10))
gf180mcu_as_sc_mcu7t3v3_.add(gdstk.Label('Y', (3.4,2.025), layer=34, texttype=10))
gf180mcu_as_sc_mcu7t3v3_.add(gdstk.Label('B', (2.532,1.812), layer=34, texttype=10))
gf180mcu_as_sc_mcu7t3v3_.add(gdstk.Label('A', (1.08,1.817), layer=34, texttype=10))
gf180mcu_as_sc_mcu7t3v3_.add(gdstk.Label('VNW', (0.3,3.92), layer=21, texttype=10))
gf180mcu_as_sc_mcu7t3v3_.add(gdstk.Label('VPW', (0.3,0), layer=204, texttype=10))

lib.write_gds('gf180mcu_as_sc_mcu7t3v3__nand2_2.gds')
